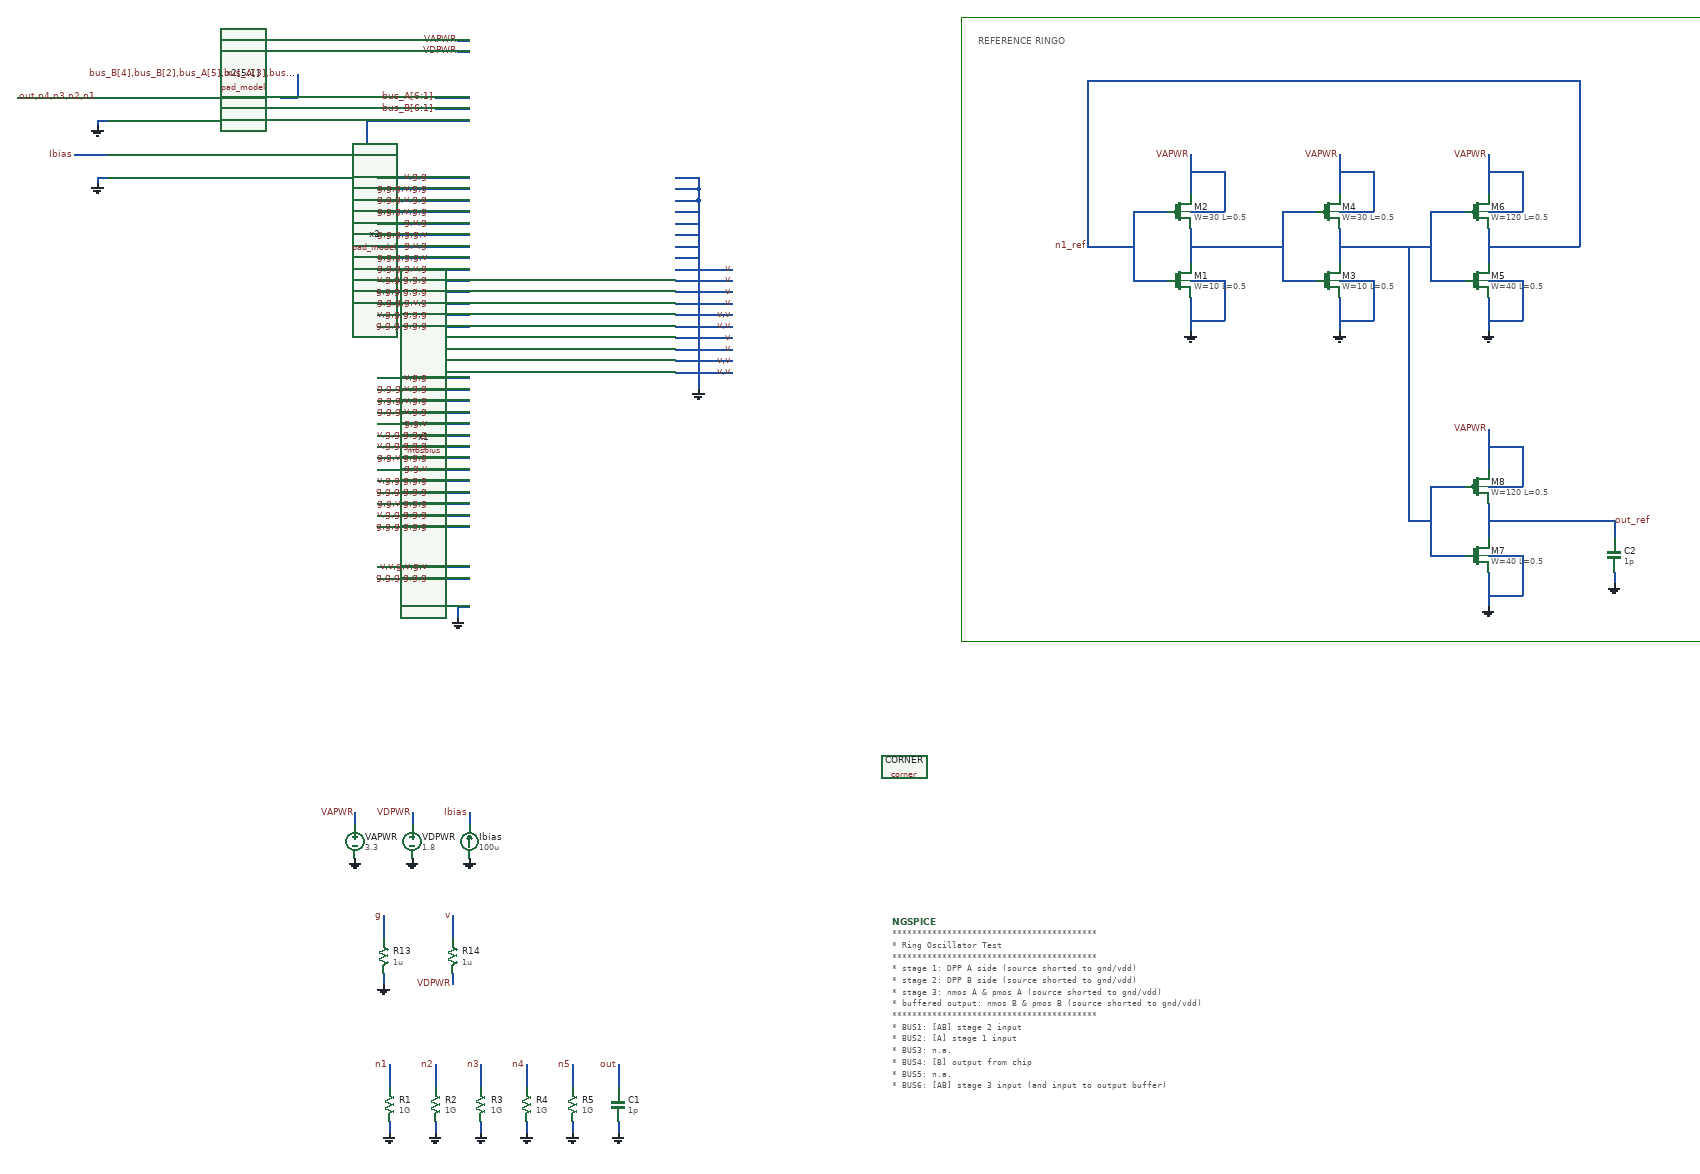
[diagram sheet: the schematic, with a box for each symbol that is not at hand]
v {xschem version=3.4.8RC file_version=1.2}
G {}
K {}
V {}
S {}
E {}
L 4 1160 -1290 2520 -1290 {}
L 4 1160 -1290 1160 -200 {}
L 4 2520 -1290 2520 -200 {}
L 4 1160 -200 2520 -200 {}
T {REFERENCE RINGO} 1190 -1260 0 0 0.4 0.4 {}
N 100 100 100 120 {
lab=VAPWR}
N 200 100 200 120 {
lab=VDPWR}
N 280 -1230 300 -1230 {
lab=VDPWR}
N 280 -1250 300 -1250 {
lab=VAPWR}
N 280 -260 280 -240 {
lab=GND}
N 280 -260 300 -260 {
lab=GND}
N 300 100 300 120 {
lab=Ibias}
N 660 -970 700 -970 {
lab=GND}
N 660 -950 700 -950 {
lab=GND}
N 660 -930 700 -930 {
lab=GND}
N 660 -910 700 -910 {
lab=GND}
N 660 -890 700 -890 {
lab=GND}
N 700 -970 700 -640 {
lab=GND}
N 660 -990 700 -990 {
lab=GND}
N 700 -990 700 -970 {
lab=GND}
N 150 380 150 400 {
lab=GND}
N 150 280 150 320 {
lab=g}
N 270 280 270 320 {
lab=v}
N 270 380 270 400 {
lab=VDPWR}
N 660 -1010 700 -1010 {
lab=GND}
N 700 -1010 700 -990 {
lab=GND}
N 660 -870 700 -870 {
lab=GND}
N 660 -850 760 -850 {
lab=v}
N 660 -830 760 -830 {
lab=v}
N 660 -810 760 -810 {
lab=v}
N 660 -790 760 -790 {
lab=v}
N 660 -730 760 -730 {
lab=v}
N 660 -710 760 -710 {
lab=v}
N 160 640 160 660 {
lab=GND}
N 160 540 160 580 {
lab=n1}
N 240 640 240 660 {
lab=GND}
N 240 540 240 580 {
lab=n2}
N 320 640 320 660 {
lab=GND}
N 320 540 320 580 {
lab=n3}
N 400 640 400 660 {
lab=GND}
N 400 540 400 580 {
lab=n4}
N 480 640 480 660 {
lab=GND}
N 480 540 480 580 {
lab=n5}
N 560 640 560 660 {
lab=GND}
N 560 540 560 580 {
lab=out}
N 660 -770 760 -770 {
lab=v,v}
N 660 -750 760 -750 {
lab=v,v}
N 660 -690 760 -690 {
lab=v,v}
N 660 -670 760 -670 {
lab=v,v}
N 1560 -920 1560 -860 {
lab=#net1}
N 1560 -800 1560 -740 {
lab=GND}
N 1560 -1050 1560 -980 {
lab=VAPWR}
N 1560 -950 1620 -950 {
lab=VAPWR}
N 1620 -1020 1620 -950 {
lab=VAPWR}
N 1560 -1020 1620 -1020 {
lab=VAPWR}
N 1560 -830 1620 -830 {
lab=GND}
N 1620 -830 1620 -760 {
lab=GND}
N 1560 -760 1620 -760 {
lab=GND}
N 1460 -950 1520 -950 {
lab=n1_ref}
N 1460 -950 1460 -830 {
lab=n1_ref}
N 1460 -830 1520 -830 {
lab=n1_ref}
N 1820 -920 1820 -860 {
lab=#net2}
N 1820 -800 1820 -740 {
lab=GND}
N 1820 -1050 1820 -980 {
lab=VAPWR}
N 1820 -950 1880 -950 {
lab=VAPWR}
N 1880 -1020 1880 -950 {
lab=VAPWR}
N 1820 -1020 1880 -1020 {
lab=VAPWR}
N 1820 -830 1880 -830 {
lab=GND}
N 1880 -830 1880 -760 {
lab=GND}
N 1820 -760 1880 -760 {
lab=GND}
N 1720 -950 1780 -950 {
lab=#net1}
N 1720 -950 1720 -830 {
lab=#net1}
N 1720 -830 1780 -830 {
lab=#net1}
N 1560 -890 1720 -890 {
lab=#net1}
N 2080 -920 2080 -860 {
lab=n1_ref}
N 2080 -800 2080 -740 {
lab=GND}
N 2080 -1050 2080 -980 {
lab=VAPWR}
N 2080 -950 2140 -950 {
lab=VAPWR}
N 2140 -1020 2140 -950 {
lab=VAPWR}
N 2080 -1020 2140 -1020 {
lab=VAPWR}
N 2080 -830 2140 -830 {
lab=GND}
N 2140 -830 2140 -760 {
lab=GND}
N 2080 -760 2140 -760 {
lab=GND}
N 1980 -950 2040 -950 {
lab=#net2}
N 1980 -950 1980 -830 {
lab=#net2}
N 1980 -830 2040 -830 {
lab=#net2}
N 1820 -890 1980 -890 {
lab=#net2}
N 2080 -890 2240 -890 {
lab=n1_ref}
N 2240 -1180 2240 -890 {
lab=n1_ref}
N 1380 -1180 2240 -1180 {
lab=n1_ref}
N 1380 -1180 1380 -890 {
lab=n1_ref}
N 1380 -890 1460 -890 {
lab=n1_ref}
N 2080 -440 2080 -380 {
lab=out_ref}
N 2080 -320 2080 -260 {
lab=GND}
N 2080 -570 2080 -500 {
lab=VAPWR}
N 2080 -470 2140 -470 {
lab=VAPWR}
N 2140 -540 2140 -470 {
lab=VAPWR}
N 2080 -540 2140 -540 {
lab=VAPWR}
N 2080 -350 2140 -350 {
lab=GND}
N 2140 -350 2140 -280 {
lab=GND}
N 2080 -280 2140 -280 {
lab=GND}
N 1980 -470 2040 -470 {
lab=#net2}
N 1980 -470 1980 -350 {
lab=#net2}
N 1980 -350 2040 -350 {
lab=#net2}
N 1940 -890 1940 -410 {
lab=#net2}
N 1940 -410 1980 -410 {
lab=#net2}
N 2080 -410 2300 -410 {
lab=out_ref}
N 2300 -320 2300 -300 {
lab=GND}
N 2300 -410 2300 -380 {
lab=out_ref}
N -490 -1150 -330 -1150 {
lab=out,n4,n3,n2,n1}
N -390 -1050 -330 -1050 {
lab=Ibias}
N 100 -1050 120 -1050 {
lab=#net3}
N 120 -1110 120 -1050 {
lab=#net3}
N 120 -1110 300 -1110 {
lab=#net3}
N -350 -1110 -350 -1100 {
lab=GND}
N -350 -1110 -330 -1110 {
lab=GND}
N 240 -1150 300 -1150 {lab=bus_A[6:1]}
N 240 -1130 300 -1130 {lab=bus_B[6:1]}
N -30 -1050 100 -1050 {lab=#net3}
N -30 -1150 0 -1150 {lab=bus_B[4],bus_B[2],bus_A[5],bus_A[3],bus_A[1]}
N 0 -1190 0 -1150 {lab=bus_B[4],bus_B[2],bus_A[5],bus_A[3],bus_A[1]}
N -350 -1010 -350 -1000 {
lab=GND}
N -350 -1010 -330 -1010 {
lab=GND}
N 140 -420 300 -420 {
lab=v,g,g,g,g,g}
N 140 -440 300 -440 {
lab=g,g,v,g,g,g}
N 140 -460 300 -460 {
lab=g,g,g,g,g,g}
N 140 -480 300 -480 {
lab=v,g,g,g,g,g}
N 140 -500 300 -500 {
lab=g,g,v}
N 140 -520 300 -520 {
lab=g,g,v,g,g,g}
N 140 -540 300 -540 {
lab=v,g,g,g,g,g}
N 140 -560 300 -560 {
lab=v,g,g,g,g,g}
N 140 -580 300 -580 {
lab=g,g,v}
N 140 -600 300 -600 {
lab=g,g,g,v,g,g}
N 140 -620 300 -620 {
lab=g,g,g,v,g,g}
N 140 -640 300 -640 {
lab=g,g,g,v,g,g}
N 140 -660 300 -660 {
lab=v,g,g}
N 140 -750 300 -750 {
lab=g,g,g,g,g,g}
N 140 -770 300 -770 {
lab=v,g,g,g,g,g}
N 140 -790 300 -790 {
lab=g,g,g,g,v,g}
N 140 -810 300 -810 {
lab=g,g,g,g,g,g}
N 140 -830 300 -830 {
lab=v,g,g,g,g,g}
N 140 -850 300 -850 {
lab=g,g,g,g,v,g}
N 140 -870 300 -870 {
lab=g,g,g,g,g,v}
N 140 -910 300 -910 {
lab=g,g,g,g,g,v}
N 140 -950 300 -950 {
lab=g,g,g,v,g,g}
N 140 -970 300 -970 {
lab=g,g,g,v,g,g}
N 140 -890 300 -890 {
lab=g,v,g}
N 140 -930 300 -930 {
lab=g,v,g}
N 140 -330 300 -330 {
lab=v,v,g,v,g,v}
N 140 -1010 300 -1010 {
lab=v,g,g}
N 140 -990 300 -990 {
lab=g,g,g,v,g,g}
N 140 -310 300 -310 {lab=g,g,g,g,g,g}
N 140 -400 300 -400 {lab=g,g,g,g,g,g}
C {mosbius.sym} 300 -240 0 0 {name=x1}
C {devices/vsource.sym} 100 150 0 0 {name=VAPWR value=3.3}
C {devices/gnd.sym} 100 180 0 0 {name=l1 lab=GND}
C {devices/lab_pin.sym} 100 100 1 0 {name=p2 sig_type=std_logic lab=VAPWR}
C {devices/vsource.sym} 200 150 0 0 {name=VDPWR value=1.8}
C {devices/gnd.sym} 200 180 0 0 {name=l2 lab=GND}
C {devices/lab_pin.sym} 200 100 1 0 {name=p3 sig_type=std_logic lab=VDPWR}
C {devices/lab_pin.sym} 280 -1250 0 0 {name=p4 sig_type=std_logic lab=VAPWR}
C {devices/lab_pin.sym} 280 -1230 0 0 {name=p5 sig_type=std_logic lab=VDPWR}
C {devices/gnd.sym} 280 -240 0 0 {name=l3 lab=GND}
C {devices/isource.sym} 300 150 2 1 {name=Ibias value=100u}
C {devices/gnd.sym} 300 180 0 0 {name=l4 lab=GND}
C {devices/lab_pin.sym} 300 100 1 0 {name=p1 sig_type=std_logic lab=Ibias}
C {devices/gnd.sym} 700 -640 0 0 {name=l5 lab=GND}
C {sky130_fd_pr/corner.sym} 1060 20 0 0 {name=CORNER only_toplevel=true corner=tt}
C {devices/code_shown.sym} 1040 290 0 0 {name=NGSPICE only_toplevel=true value=
"
*****************************************
* Ring Oscillator Test
*****************************************
* stage 1: DPP A side (source shorted to gnd/vdd)
* stage 2: DPP B side (source shorted to gnd/vdd)
* stage 3: nmos A & pmos A (source shorted to gnd/vdd)
* buffered output: nmos B & pmos B (source shorted to gnd/vdd)
*****************************************
* BUS1: [AB] stage 2 input
* BUS2: [A]  stage 1 input
* BUS3: n.a.
* BUS4: [B] output from chip
* BUS5: n.a.
* BUS6: [AB] stage 3 input (and input to output buffer)
*****************************************
.nodeset v(n1)=0
.nodeset v(n1_ref)=0
.control
   save all
   set temp = 27
   tran 100p 500n UIC
   plot v(out)
   plot v(out_ref)
.endc
"}
C {devices/gnd.sym} 150 400 0 0 {name=l10 lab=GND}
C {devices/res.sym} 150 350 0 0 {name=R13
value=1u
footprint=1206
device=resistor
m=1}
C {devices/lab_pin.sym} 150 280 0 0 {name=p17 sig_type=std_logic lab=g}
C {devices/res.sym} 270 350 0 0 {name=R14
value=1u
footprint=1206
device=resistor
m=1}
C {devices/lab_pin.sym} 270 400 3 0 {name=p18 sig_type=std_logic lab=VDPWR}
C {devices/lab_pin.sym} 270 280 0 0 {name=p19 sig_type=std_logic lab=v}
C {devices/lab_wire.sym} 760 -850 0 0 {name=p14 sig_type=std_logic lab=v}
C {devices/lab_wire.sym} 760 -830 0 0 {name=p43 sig_type=std_logic lab=v}
C {devices/lab_wire.sym} 760 -810 0 0 {name=p44 sig_type=std_logic lab=v}
C {devices/lab_wire.sym} 760 -790 0 0 {name=p66 sig_type=std_logic lab=v}
C {devices/lab_wire.sym} 760 -730 0 0 {name=p67 sig_type=std_logic lab=v}
C {devices/lab_wire.sym} 760 -710 0 0 {name=p68 sig_type=std_logic lab=v}
C {devices/gnd.sym} 160 660 0 0 {name=l7 lab=GND}
C {devices/res.sym} 160 610 0 0 {name=R1
value=1G
footprint=1206
device=resistor
m=1}
C {devices/lab_pin.sym} 160 540 0 0 {name=p12 sig_type=std_logic lab=n1}
C {devices/gnd.sym} 240 660 0 0 {name=l8 lab=GND}
C {devices/res.sym} 240 610 0 0 {name=R2
value=1G
footprint=1206
device=resistor
m=1}
C {devices/lab_pin.sym} 240 540 0 0 {name=p13 sig_type=std_logic lab=n2}
C {devices/gnd.sym} 320 660 0 0 {name=l11 lab=GND}
C {devices/res.sym} 320 610 0 0 {name=R3
value=1G
footprint=1206
device=resistor
m=1}
C {devices/lab_pin.sym} 320 540 0 0 {name=p23 sig_type=std_logic lab=n3}
C {devices/gnd.sym} 400 660 0 0 {name=l17 lab=GND}
C {devices/res.sym} 400 610 0 0 {name=R4
value=1G
footprint=1206
device=resistor
m=1}
C {devices/lab_pin.sym} 400 540 0 0 {name=p26 sig_type=std_logic lab=n4}
C {devices/gnd.sym} 480 660 0 0 {name=l18 lab=GND}
C {devices/res.sym} 480 610 0 0 {name=R5
value=1G
footprint=1206
device=resistor
m=1}
C {devices/lab_pin.sym} 480 540 0 0 {name=p29 sig_type=std_logic lab=n5}
C {devices/capa.sym} 560 610 0 0 {name=C1
m=1
value=1p
footprint=1206
device="ceramic capacitor"}
C {devices/gnd.sym} 560 660 0 0 {name=l6 lab=GND}
C {devices/lab_pin.sym} 560 540 0 0 {name=p8 sig_type=std_logic lab=out}
C {devices/lab_wire.sym} 760 -770 0 0 {name=p10 sig_type=std_logic lab=v,v}
C {devices/lab_wire.sym} 760 -750 0 0 {name=p28 sig_type=std_logic lab=v,v}
C {devices/lab_wire.sym} 760 -690 0 0 {name=p30 sig_type=std_logic lab=v,v}
C {devices/lab_wire.sym} 760 -670 0 0 {name=p31 sig_type=std_logic lab=v,v}
C {sky130_fd_pr/nfet_g5v0d10v5.sym} 1540 -830 0 0 {name=M1
L=0.5
W=10
nf=2
mult=1
ad="'int((nf+1)/2) * W/nf * 0.29'" 
pd="'2*int((nf+1)/2) * (W/nf + 0.29)'"
as="'int((nf+2)/2) * W/nf * 0.29'" 
ps="'2*int((nf+2)/2) * (W/nf + 0.29)'"
nrd="'0.29 / W'" nrs="'0.29 / W'"
sa=0 sb=0 sd=0
model=nfet_g5v0d10v5
spiceprefix=X
}
C {sky130_fd_pr/pfet_g5v0d10v5.sym} 1540 -950 0 0 {name=M2
L=0.5
W=30
nf=4
mult=1
ad="'int((nf+1)/2) * W/nf * 0.29'" 
pd="'2*int((nf+1)/2) * (W/nf + 0.29)'"
as="'int((nf+2)/2) * W/nf * 0.29'" 
ps="'2*int((nf+2)/2) * (W/nf + 0.29)'"
nrd="'0.29 / W'" nrs="'0.29 / W'"
sa=0 sb=0 sd=0
model=pfet_g5v0d10v5
spiceprefix=X
}
C {devices/gnd.sym} 1560 -740 0 0 {name=l12 lab=GND}
C {devices/lab_pin.sym} 1560 -1050 1 0 {name=p32 sig_type=std_logic lab=VAPWR}
C {sky130_fd_pr/nfet_g5v0d10v5.sym} 1800 -830 0 0 {name=M3
L=0.5
W=10
nf=2
mult=1
ad="'int((nf+1)/2) * W/nf * 0.29'" 
pd="'2*int((nf+1)/2) * (W/nf + 0.29)'"
as="'int((nf+2)/2) * W/nf * 0.29'" 
ps="'2*int((nf+2)/2) * (W/nf + 0.29)'"
nrd="'0.29 / W'" nrs="'0.29 / W'"
sa=0 sb=0 sd=0
model=nfet_g5v0d10v5
spiceprefix=X
}
C {sky130_fd_pr/pfet_g5v0d10v5.sym} 1800 -950 0 0 {name=M4
L=0.5
W=30
nf=4
mult=1
ad="'int((nf+1)/2) * W/nf * 0.29'" 
pd="'2*int((nf+1)/2) * (W/nf + 0.29)'"
as="'int((nf+2)/2) * W/nf * 0.29'" 
ps="'2*int((nf+2)/2) * (W/nf + 0.29)'"
nrd="'0.29 / W'" nrs="'0.29 / W'"
sa=0 sb=0 sd=0
model=pfet_g5v0d10v5
spiceprefix=X
}
C {devices/gnd.sym} 1820 -740 0 0 {name=l13 lab=GND}
C {devices/lab_pin.sym} 1820 -1050 1 0 {name=p33 sig_type=std_logic lab=VAPWR}
C {sky130_fd_pr/nfet_g5v0d10v5.sym} 2060 -830 0 0 {name=M5
L=0.5
W=40
nf=2
mult=1
ad="'int((nf+1)/2) * W/nf * 0.29'" 
pd="'2*int((nf+1)/2) * (W/nf + 0.29)'"
as="'int((nf+2)/2) * W/nf * 0.29'" 
ps="'2*int((nf+2)/2) * (W/nf + 0.29)'"
nrd="'0.29 / W'" nrs="'0.29 / W'"
sa=0 sb=0 sd=0
model=nfet_g5v0d10v5
spiceprefix=X
}
C {sky130_fd_pr/pfet_g5v0d10v5.sym} 2060 -950 0 0 {name=M6
L=0.5
W=120
nf=4
mult=1
ad="'int((nf+1)/2) * W/nf * 0.29'" 
pd="'2*int((nf+1)/2) * (W/nf + 0.29)'"
as="'int((nf+2)/2) * W/nf * 0.29'" 
ps="'2*int((nf+2)/2) * (W/nf + 0.29)'"
nrd="'0.29 / W'" nrs="'0.29 / W'"
sa=0 sb=0 sd=0
model=pfet_g5v0d10v5
spiceprefix=X
}
C {devices/gnd.sym} 2080 -740 0 0 {name=l16 lab=GND}
C {devices/lab_pin.sym} 2080 -1050 1 0 {name=p34 sig_type=std_logic lab=VAPWR}
C {sky130_fd_pr/nfet_g5v0d10v5.sym} 2060 -350 0 0 {name=M7
L=0.5
W=40
nf=2
mult=1
ad="'int((nf+1)/2) * W/nf * 0.29'" 
pd="'2*int((nf+1)/2) * (W/nf + 0.29)'"
as="'int((nf+2)/2) * W/nf * 0.29'" 
ps="'2*int((nf+2)/2) * (W/nf + 0.29)'"
nrd="'0.29 / W'" nrs="'0.29 / W'"
sa=0 sb=0 sd=0
model=nfet_g5v0d10v5
spiceprefix=X
}
C {sky130_fd_pr/pfet_g5v0d10v5.sym} 2060 -470 0 0 {name=M8
L=0.5
W=120
nf=4
mult=1
ad="'int((nf+1)/2) * W/nf * 0.29'" 
pd="'2*int((nf+1)/2) * (W/nf + 0.29)'"
as="'int((nf+2)/2) * W/nf * 0.29'" 
ps="'2*int((nf+2)/2) * (W/nf + 0.29)'"
nrd="'0.29 / W'" nrs="'0.29 / W'"
sa=0 sb=0 sd=0
model=pfet_g5v0d10v5
spiceprefix=X
}
C {devices/gnd.sym} 2080 -260 0 0 {name=l19 lab=GND}
C {devices/lab_pin.sym} 2080 -570 1 0 {name=p35 sig_type=std_logic lab=VAPWR}
C {devices/capa.sym} 2300 -350 0 0 {name=C2
m=1
value=1p
footprint=1206
device="ceramic capacitor"}
C {devices/gnd.sym} 2300 -300 0 0 {name=l20 lab=GND}
C {devices/lab_pin.sym} 2300 -410 0 1 {name=p36 sig_type=std_logic lab=out_ref}
C {devices/lab_pin.sym} 1380 -890 0 0 {name=p37 sig_type=std_logic lab=n1_ref}
C {pad_model.sym} -180 -1130 0 0 {name=x2[5:1]}
C {devices/lab_wire.sym} -350 -1150 0 0 {name=p9 sig_type=std_logic lab=out,n4,n3,n2,n1}
C {pad_model.sym} -180 -1030 0 0 {name=x2}
C {devices/lab_pin.sym} -390 -1050 0 0 {name=p6 sig_type=std_logic lab=Ibias}
C {devices/gnd.sym} -350 -1100 0 0 {name=l14 lab=GND}
C {devices/lab_wire.sym} 240 -1150 0 0 {name=p11 sig_type=std_logic lab=bus_A[6:1]}
C {devices/lab_wire.sym} 240 -1130 0 0 {name=p56 sig_type=std_logic lab=bus_B[6:1]}
C {devices/lab_wire.sym} 0 -1190 0 0 {name=p64 sig_type=std_logic lab=bus_B[4],bus_B[2],bus_A[5],bus_A[3],bus_A[1]}
C {devices/gnd.sym} -350 -1000 0 0 {name=l9 lab=GND}
C {devices/lab_wire.sym} 230 -500 0 0 {name=p27 sig_type=std_logic lab=g,g,v}
C {devices/lab_wire.sym} 230 -640 0 0 {name=p7 sig_type=std_logic lab=g,g,g,v,g,g}
C {devices/lab_wire.sym} 230 -660 0 0 {name=p45 sig_type=std_logic lab=v,g,g}
C {devices/lab_wire.sym} 230 -890 0 0 {name=p57 sig_type=std_logic lab=g,v,g}
C {devices/lab_wire.sym} 230 -330 0 0 {name=p25 sig_type=std_logic lab=v,v,g,v,g,v}
C {devices/lab_wire.sym} 230 -1010 0 0 {name=p15 sig_type=std_logic lab=v,g,g}
C {devices/lab_wire.sym} 230 -310 0 0 {name=p65 sig_type=std_logic lab=g,g,g,g,g,g}
C {devices/lab_wire.sym} 230 -770 0 0 {name=p16 sig_type=std_logic lab=v,g,g,g,g,g}
C {devices/lab_wire.sym} 230 -790 0 0 {name=p47 sig_type=std_logic lab=g,g,g,g,v,g}
C {devices/lab_wire.sym} 230 -810 0 0 {name=p48 sig_type=std_logic lab=g,g,g,g,g,g}
C {devices/lab_wire.sym} 230 -830 0 0 {name=p49 sig_type=std_logic lab=v,g,g,g,g,g}
C {devices/lab_wire.sym} 230 -850 0 0 {name=p50 sig_type=std_logic lab=g,g,g,g,v,g}
C {devices/lab_wire.sym} 230 -870 0 0 {name=p51 sig_type=std_logic lab=g,g,g,g,g,v}
C {devices/lab_wire.sym} 230 -950 0 0 {name=p52 sig_type=std_logic lab=g,g,g,v,g,g}
C {devices/lab_wire.sym} 230 -970 0 0 {name=p54 sig_type=std_logic lab=g,g,g,v,g,g}
C {devices/lab_wire.sym} 230 -990 0 0 {name=p55 sig_type=std_logic lab=g,g,g,v,g,g}
C {devices/lab_wire.sym} 230 -620 0 0 {name=p20 sig_type=std_logic lab=g,g,g,v,g,g}
C {devices/lab_wire.sym} 230 -600 0 0 {name=p21 sig_type=std_logic lab=g,g,g,v,g,g}
C {devices/lab_wire.sym} 230 -560 0 0 {name=p22 sig_type=std_logic lab=v,g,g,g,g,g}
C {devices/lab_wire.sym} 230 -540 0 0 {name=p24 sig_type=std_logic lab=v,g,g,g,g,g}
C {devices/lab_wire.sym} 230 -520 0 0 {name=p38 sig_type=std_logic lab=g,g,v,g,g,g}
C {devices/lab_wire.sym} 230 -480 0 0 {name=p39 sig_type=std_logic lab=v,g,g,g,g,g}
C {devices/lab_wire.sym} 230 -460 0 0 {name=p40 sig_type=std_logic lab=g,g,g,g,g,g}
C {devices/lab_wire.sym} 230 -440 0 0 {name=p42 sig_type=std_logic lab=g,g,v,g,g,g}
C {devices/lab_wire.sym} 230 -420 0 0 {name=p59 sig_type=std_logic lab=v,g,g,g,g,g}
C {devices/lab_wire.sym} 230 -400 0 0 {name=p60 sig_type=std_logic lab=g,g,g,g,g,g}
C {devices/lab_wire.sym} 230 -930 0 0 {name=p58 sig_type=std_logic lab=g,v,g}
C {devices/lab_wire.sym} 230 -580 0 0 {name=p41 sig_type=std_logic lab=g,g,v}
C {devices/lab_wire.sym} 230 -750 0 0 {name=p46 sig_type=std_logic lab=g,g,g,g,g,g}
C {devices/lab_wire.sym} 230 -910 0 0 {name=p53 sig_type=std_logic lab=g,g,g,g,g,v}
